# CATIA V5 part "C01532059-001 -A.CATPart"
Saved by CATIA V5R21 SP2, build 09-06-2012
Part number: C01532059-001
Revision: ---
Description: PROPRIETARY NOTICE (do not delete / modify)  ***************************************************************************************************  LA SOCIETE EN COMMANDITE  AIRBUS CANADA  ("AIRBUS CANADA")  PAR  L'INTERMEDIAIRE  DE  SES  DIVISIONS  ET/OU  FILIALES  CORPORATIVES,  FOURNIT  LES PRESENTES  INFORMATIONS  AU  GOUVERNEMENT  A  TITRE CONFIDENTIEL. CES  INFORMATIONS ONT UNE TENEUR CONFIDENTIELLE,  AVEC DROITS DE PROPRIETE,  ET NOUS LES CONSIDERONS  EXCLUS  DE   L'APPLICATION  DE  LA LOI SUR L'ACCES A L'INFORMATION  (CANADA),  LES  LOIS  SUR  L'ACCES  A  L'INFORMATION  EUROPEENNES,  LE FREEDOM OF INFORMATION ACT (ETATS-UNIS) ET D'AUTRES LOIS SEMBLABLES. ELLES  PEUVENT  AUSSI  CONSTITUER DES SECRETS INDUSTRIELS DE NOTRE SOCIETE OU DE TIERCES PARTIES. LA DIVULGATION  PUBLIQUE  DE CES  INFORMATIONS NUIRAIT A AIRBUS CANADA OU A DES TIERCES PARTIES.  CES INFORMATIONS PEUVENT EGALEMENT CONTENIR  DES DONNEES QUI SONT CONTROLEE PAR DES LOIS DE CONTROLE DES EXPORTATIONS DU CANADA, L’EUROPE OU LES  ETATS-  UNIS. TOUTE EXPORTATION OU REEXPORTATION DE DONNEES CONTROLEES SANS AUTORISATION EST STRICTEMENT INTERDITE.  TOUTE INTENTION DE LES DIVULGUER EN TOUT OU EN PARTIE DEVRA ETRE SIGNIFIEE A L'AVANCE ET PAR ECRIT AU VICE-  PRESIDENT, SERVICES JURIDIQUES ET CONFORMITE ET SECRETAIRE CORPORATIF D'AIRBUS CANADA.    AIRBUS CANADA LIMITED PARTNERSHIP  ("AIRBUS CANADA"),  BY ITS AFFILIATES AND/OR SUBSIDIARIES, PROVIDES THIS  INFORMATION TO THE GOVERNMENT IN CONFIDENCE. THIS IS PROPRIETARY CONFIDENTIAL INFORMATION WHICH WE CONSIDER  EXCLUDED  FROM  THE  APPLICATION OF THE ACCESS TO INFORMATION ACT (CANADA),  THE FREEDOM OF INFORMATION ACT  (U.S.A.),  THE ACCESS TO INFORMATION LAWS IN EUROPE, AND OTHER SIMILAR LEGISLATION. AND MAY ALSO CONSTITUTE  TRADE SECRETS OF OUR  COMPANY OR THIRD PARTIES.  PUBLIC  RELEASE  OF  THIS INFORMATION  WOULD BE HARMFUL TO  AIRBUS CANADA OR THIRD PARTIES.  THIS  INFORMATION  MAY  ALSO  CONTAIN DATA THAT IS CONTROLLED BY CANADIAN,  EUROPEAN, OR U.S.A. EXPORT CONTROL LAWS. ANY UNAUTHORIZED EXPORT OR RE-EXPORT OF ANY EXPORT CONTROLLED DATA  IS STRICTLY PROHIBITED  ANY INTENTION TO DISCLOSE SUCH INFORMATION,  OR  PART THEREOF,  MUST BE NOTIFIED IN  ADVANCE AND IN WRITING TO THE VICE PRESIDENT, LEGAL AND COMPLIANCE AND CORPORATE SECRETARY OF AIRBUS CANADA.        LES RENSEIGNEMENTS,  LES DONNEES  ET  DESSINS  TECHNIQUES  DIVULGUES  DANS  LES PRESENTES SONT LA PROPRIETE  EXCLUSIVE DE LA SOCIETE EN COMMANDITE AIRBUS CANADA ("AIRBUS CANADA") OU COMPORTENT DES DROITS DE PROPRIETE  APPARTENANT  A  AUTRUI ET NE PEUVENT ETRE DIVULGUES  A  QUICONQUE  NI  UTILISES PAR QUI QUE CE SOIT SANS LE  CONSENTEMENT  ECRIT  D’AIRBUS  CANADA.  LE DETENTEUR DES  PRESENTES  S'ENGAGE, DANS TOUTES CIRCONSTANCES, A  GARDER CONFIDENTIELS LES DONNEES ET DESSINS TECHNIQUES QU'ELLES CONTIENNENT.   CE QUI PRECEDE NE S'APPLIQUE  PAS  AUX PERSONNES  QUI  ONT DES DROITS DE PROPRIETE SUR CES RENSEIGNEMENTS,  DONNEES TECHNIQUES ET DESSINS  DANS LA MESURE OU CES DROITS EXISTENT.    THE INFORMATION,  TECHNICAL DATA  AND  DESIGNS DISCLOSED HEREIN ARE THE EXCLUSIVE PROPERTY OF AIRBUS CANADA  LIMITED PARTNERSHIP  ("AIRBUS CANADA")  OR  CONTAIN PROPRIETARY RIGHTS OF OTHERS  AND ARE NOT TO BE USED OR  DISCLOSED  TO  OTHERS WITHOUT THE WRITTEN CONSENT OF AIRBUS CANADA.  THE RECIPIENT OF THIS DOCUMENT, BY ITS  RETENTION  AND  USE  AGREES TO  HOLD  IN  CONFIDENCE  THE  TECHNICAL DATA AND DESIGNS CONTAINED HEREIN. THE  FOREGOING SHALL NOT APPLY TO PERSONS HAVING PROPRIETARY RIGHTS TO SUCH INFORMATION,  TECHNICAL DATA OR SUCH  DESIGNS TO THE EXTENT THAT SUCH RIGHTS EXIST.    Copyright 2020 Airbus Canada Limited Partnership. All Rights Reserved.  ***********************************
Property "Title": "LEVER, LIFT, AFT PASS DR"
Property "Dataset Type": "DETAIL"
Property "Supplier Name And CAGE Code": "AIRBUS CANADA LIMITED PARTNERSHIP L0J48"
Property "Major Supplier Code": "LP"
Property "3D Only": "N/A"
Property "Material Form": "BAR - FLAT"
Property "Finish Code": "S010"
Property "PCCN": "2"
Property "Organization": "DESIGN"
Property "Design Authority Program": "BD-500"
Property "Color Coded": "N/A"
Property "Thickness": 1.5
Property "Inside Diameter": 0
Property "Outside Diameter": 0
Property "Length": 0
Property "Width": 3.75
Property "Wall": 0
Property "Wire Gauge": "-"
Property "Alloy": "PH13-8MO"
Property "Final Condition": "H1000"
Property "Density": "N/A"
Property "Form": "N/A"
Property "Grade/Composition": "N/A"
Property "Material Class": "N/A"
Property "Mesh Cell Size": "N/A"
Property "Standard Spec Die": "N/A"
Property "Type": "N/A"
Property "Style": "N/A"
Property "MFG Process": "MACHINED"
Property "Material Specification Production": "AMS5629"
Property "Material Description Production": "CRES"
Property "Dimensions": "DIMENSIONS ARE IN INCHES"
Property "Roughness": "ALL MACHINED SURFACES 125 Ra MAX"
Property "Eng. Tolerances": "LINEAR .XX= +/-.03; .XXX= +/-.010; ANGULAR= +/-0.5 DEG"
Property "Tool Design Tolerances": "LINEAR .X= +/-.06; .XX= +/-.015; .XXX= +/-.005; .XXXX= +/-.001; ANGULAR= +/-0.5 DEG"
Property "Project": "BA"
Publications: "PartBody", "REFERENCE ORIENTATION", "REFERENCE PLANE", "REFERENCE AXIS", "Extract.1_Datum_A", "Extract.1_Datum_B", "Extract.1_Datum_C", "Extract.1_Datum_D"
Material "CRES-PH-13-8-MO-BAR": density 7750.37 kg/m3
Bounding box of the stored display mesh (mm): x -166.37 to 0, y -15.24 to 15.24, z -21.948 to 69.533
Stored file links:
  C:\Users\CQQZ006\Desktop\A220钢钛件\舱门\C01532059-001\C01532059-001 -A.CATPart
  I:\Standard\Materials\Textures\steel100.jpeg

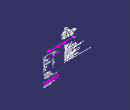
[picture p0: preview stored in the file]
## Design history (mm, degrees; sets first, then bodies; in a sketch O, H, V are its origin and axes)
Part_3D_Annotations1 "CATTPSSet"
AxisSystem1: origin (0, 0, 0), X (1, 0, 0), Y (0, 1, 0), Z (0, 0, 1)
Set1 "Pilot_Holes"
  Set2 "5/32"
    Line1 "Fix Orientation 1": stored without definition
    Point1 "Fix Point 1": stored without definition
  Set3 "1/4"
    Set4 "Copied From C01512050-001"
      Line2 "Fix Orientation 1": stored without definition
      Line3 "Fix Orientation 2": stored without definition
      Point2 "Fix Point 1": stored without definition
      Point3 "Fix Point 2": stored without definition
Set5 "References"
  Line4 "REFERENCE ORIENTATION": type PtDir, RefPoint Point4, Direction yz-plane, Start -25.4, End 6.35
  Plane1 "REFERENCE PLANE": type Offset, RefPlane face of Shaft1 from Sketch1.L8, Offset 0, reversed
  Line5 "REFERENCE AXIS": type PtPt, FirstPoint Point5, SecondPoint Point6
Set6 "Geometrical Set for 3D Annotations"
  Set7 "No Show Geometry"
    Extract1 "Extract.1_Datum_A": ExtractElem face of Shaft1 from Sketch1.L9
    Extract2 "Extract.1_Datum_B": ExtractElem face of Shaft1 from Sketch1.L19
    Extract3 "Extract.1_Datum_C": ExtractElem face of Pocket1 from Sketch2.A3
    Extract4 "Extract.1_Datum_D": ExtractElem end face of Pocket2
Set8 "Construction_Geometry"
  Point4: type Center, Curve edge [face of Chamfer1 | face of Shaft1 from Sketch1.L1]
  Point5: type Center, Curve edge [end face of Pocket2 | face of Shaft1 from Sketch1.L10]
  Point6: type Center, Curve edge [face of Shaft1 from Sketch1.L7 | face of Shaft1 from Sketch1.L12]
Body1 (main body)
  Sketch1 on zx-plane, origin (0, 0, 0), H (-1, 0, 0), V (0, 0, 1)
    line L1 (0, 7.9375) -> (0, 76.2)
    line L2 (0, 76.2) -> (15.24, 76.2)
    line L3 (15.24, 76.2) -> (15.24, 20.828)
    arc A1 centre (20.828, 20.828) radius 5.588 from (15.24, 20.828) to (20.828, 15.24) ccw
    line L4 (20.828, 15.24) -> (30.6324, 15.24)
    point P6 (56.388, 12.6784)
    arc A2 centre (60.2873, 24.765) radius 12.7 from (56.388, 12.6784) to (60.2873, 12.065) ccw
    line L5 (60.2873, 12.065) -> (98.4627, 12.065)
    arc A3 centre (98.4627, 24.765) radius 12.7 from (98.4627, 12.065) to (102.362, 12.6784) ccw
    line L6 (146.304, 7.9223) -> (166.37, 7.9223)
    point P11 (166.37, 7.9223)
    line L7 (166.37, 7.9223) -> (166.37, 4.7625)
    line L8 (146.05, 8.1763) -> (146.05, 12.6784)
    point P12 (146.05, 12.6784)
    line L9 (146.05, 12.6784) -> (102.362, 12.6784)
    point P13 (102.362, 12.6784)
    line L10 (0, 7.9375) -> (140.462, 7.9375)
    point P14 (140.462, 7.9375)
    line L11 (140.462, 7.9375) -> (142.2951, 4.7625)
    line L12 (142.2951, 4.7625) -> (166.37, 4.7625)
    construction line L13 (116.4249, -12.6784) -> (142.4659, -12.6784)
    construction line L14 (161.544, -9.5072) -> (167.3073, -9.5072)
    construction line L15 (23.5752, -15.24) -> (37.3676, -15.24)
    construction line L16 (104.394, 13.7142) -> (104.394, 7.238)
    construction line L17 (54.356, 16.6102) -> (54.356, 11.0857)
    line L18 (30.6324, 15.24) -> (30.6324, 12.9324)
    line L19 (30.8864, 12.6784) -> (56.388, 12.6784)
    point P29 (146.05, 7.9223)
    arc A4 centre (146.304, 8.1763) radius 0.254 from (146.304, 7.9223) to (146.05, 8.1763) cw
    arc A5 centre (30.8864, 12.9324) radius 0.254 from (30.6324, 12.9324) to (30.8864, 12.6784) ccw
    distance H L2 = 76.2
    distance L5 H = 12.065
    radius A3 = 12.7
    radius A2 = 12.7
    length L2 = 15.24
    radius A1 = 5.588
    distance L6 H = 7.9223
    distance P6 V = 56.388
    distance L1 L8 = 146.05
    length L9 = 43.688
    distance L10 H = 7.9375
    distance P12 P14 H = 5.588
    distance L12 H = 4.7625
    angle L11 L12 = 60
    distance L10 L5 = 4.1275 (reference)
    distance L13 L9 = 25.3568
    distance L15 L4 = 30.48
    distance L16 P13 = 2.032
    distance L17 P6 = 2.032
    distance L18 L3 = 15.3924
    distance P29 P11 = 20.32
    radius A4 = 0.254
    radius A5 = 0.254
    distance L19 H = 12.6784
    vertical: L1 V, L3 V, L7 V, L8 V, L16 V, L17 V, L18 V
    horizontal: L2 H, L5 H, L6 H, L9 H, L10 H, L12 H, L13 H, L14 H, L15 H, L19 H
    tangency: A1 L3, L4 A1, A3 L5, A2 L5, A4 L6, A4 L8, A5 L18, A5 L19
    coincidence: O L1, L6 P29, L8 P29
    symmetry: L13 L9 H, L15 L4 H
  Shaft1: profile Sketch1, axis Sketch1.H, angle 360
  Body2
    Sketch2 on yz-plane, origin (0, 0, 0), H (0, 1, 0), V (0, 0, -1)
      arc A1 centre (0, 0) radius 15.24 from (15.2019, -1.0767) to (-15.2019, -1.0767) ccw
      construction line L1 (0, 0) -> (0, -58.42)
      arc A2 centre (0, -58.42) radius 11.1125 from (-11.0847, -59.2051) to (11.0847, -59.2051) ccw
      line L2 (-15.2019, -1.0767) -> (-11.0847, -59.2051)
      line L3 (15.2019, -1.0767) -> (11.0847, -59.2051)
      circle A3 centre (0, -58.42) radius 5.5632
      projected circle E1 centre (0, 0) radius 76.2 from edge [face of Shaft1 from Sketch1.L1 | face of Shaft1 from Sketch1.L2]
      length L1 = 58.42
      radius A2 = 11.1125
      radius A1 = 15.24
      radius A3 = 5.5632
      tangency: L2 A2, L2 A1, L3 A2, L3 A1
      coincidence: L1 V
    Pocket1: profile Sketch2, direction (1, 0, 0), length 5.08, opposite side length 25.4
  Assemble1: tool Body2
  Body3
    Sketch3 on yz-plane, origin (0, 0, 0), H (0, 1, 0), V (0, 0, 1)
      line L1 (-25.4, 76.2) -> (25.4, 76.2)
      line L2 (25.4, 76.2) -> (25.4, -25.4)
      line L3 (25.4, -25.4) -> (-25.4, -25.4)
      line L4 (-25.4, -25.4) -> (-25.4, 76.2)
      circle A1 centre (0, 58.42) radius 11.1125
      point P5 (0, 58.42)
      point P6 (0, 47.3075)
      reference projected arc E1 centre (0, 58.42) radius 11.1125 from (11.046, 59.6339) to (-11.046, 59.6339) ccw from edge [face of Shaft1 from Sketch1.L1 | face of Pocket1 from Sketch2.A2]
      distance L1 H = 76.2
      distance V L2 = 25.4
      distance V L4 = 25.4 {= Sketch3.distance(V L2)}
      distance H L3 = 25.4 {= Sketch3.distance(V L2)}
      horizontal: L1 H, L3 H
      vertical: L2 V, L4 V
      coincidence: P5 V, A1 P6, P6 V, A1 E1
    Pocket2: profile Sketch3, direction (-1, 0, 0), length 2.54
    Fillet1: radius 1.524, on edge [face of Pocket2 from Sketch3.A1 | end face of Pocket2]
  Assemble2: tool Body3
  Body4
    Sketch4 on yz-plane, origin (0, 0, 0), H (0, 1, 0), V (0, 0, 1)
      arc A1 centre (0, 0) radius 19.0284 from (0.4134, 19.0239) to (-0.4134, 19.0239) ccw
      line L1 (-6.5875, 41.81) -> (-7.6622, 26.6367)
      line L2 (6.5875, 41.81) -> (7.6622, 26.6367)
      reference intersected line E1 (-11.1082, 58.8733) -> (-15.2323, 0.6477) from face of Pocket1 from Sketch2.L2
      reference intersected line E2 (15.2323, 0.6477) -> (11.1082, 58.8733) from face of Pocket1 from Sketch2.L3
      reference projected circle E3 centre (0, 0) radius 12.6784 from edge [face of Shaft1 from Sketch1.L19 | face of Shaft1 from Sketch1.A2]
      arc A2 centre (0.568, 26.1342) radius 7.112 from (0.4134, 19.0239) to (7.6622, 26.6367) ccw
      arc A3 centre (-0.568, 26.1342) radius 7.112 from (-0.4134, 19.0239) to (-7.6622, 26.6367) cw
      arc A4 centre (0, 41.3434) radius 6.604 from (-6.5875, 41.81) to (6.5875, 41.81) cw
      construction circle A5 centre (0.568, 26.1342) radius 13.462
      point P12 (0.2755, 12.6754)
      distance L1 E1 = 5.715 {= Sketch4.distance(L2 E2)}
      distance L2 E2 = 5.715
      radius A2 = 7.112
      radius A3 = 7.112
      radius A4 = 6.604
      radius A5 = 13.462
      tangency: A2 A1, A2 L2, A3 A1, A3 L1, A4 L1, A4 L2, A5 E3
      coincidence: A5 P12, P12 E3
    Pocket3: profile Sketch4, direction (-1, 0, 0), length 25.4, opposite side up to end face of Pocket2, offset -5.715
    Fillet2: radius 1.524, on edge [start face of Pocket3 | face of Pocket3 from Sketch4.L1]
  Assemble3: tool Body4
  Chamfer1: length 1.016, angle 45, on edge [face of Shaft1 from Sketch1.L6 | face of Shaft1 from Sketch1.L7]; edge [face of Pocket2 from Sketch3.A1 | face of Shaft1 from Sketch1.L1]; edge [face of Shaft1 from Sketch1.L9 | face of Shaft1 from Sketch1.L8]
